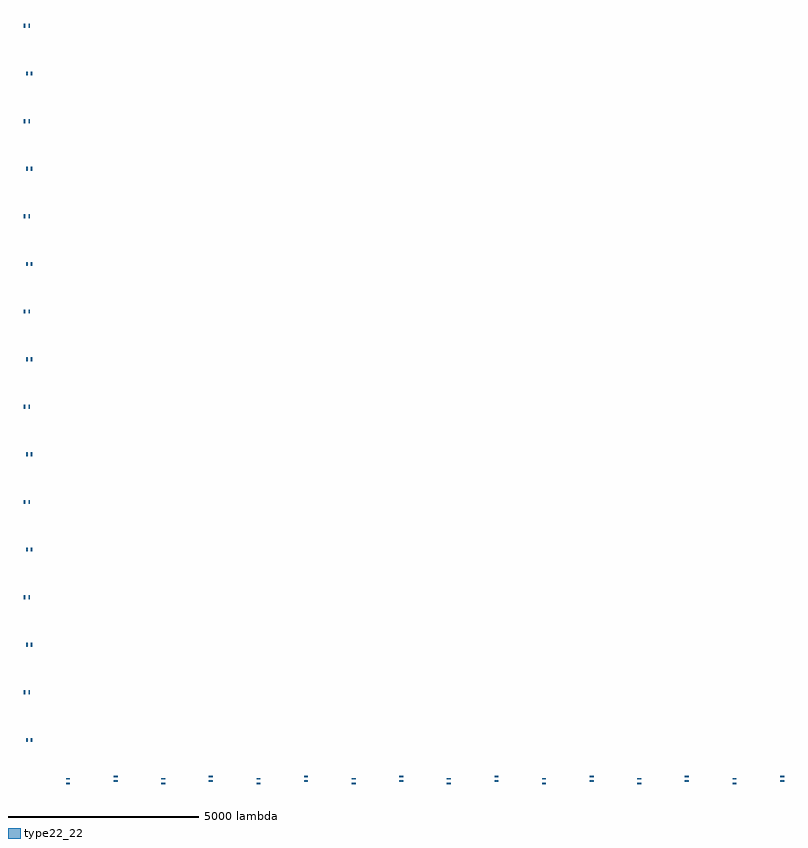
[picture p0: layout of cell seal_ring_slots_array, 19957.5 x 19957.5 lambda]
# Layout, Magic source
magic
tech sky130seal_ring
magscale 1 2
use sealring_slots  sealring_slots_Y
array 0 7 5000 0 0 430
transform 0 -1 1000 1 0 -7000
box 9500 285 12200 715
use sealring_slots  sealring_slots_X
array 0 7 5000 0 0 430
transform 1 0 -7000 0 1 0
box 9500 285 12200 715
<< end >>

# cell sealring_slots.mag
magic
tech sky130seal_ring
magscale 1 2
<< type22_22 >>
rect 12000 645 12200 715
rect 9500 525 9700 595
rect 12000 405 12200 475
rect 9500 285 9700 355
<< end >>
